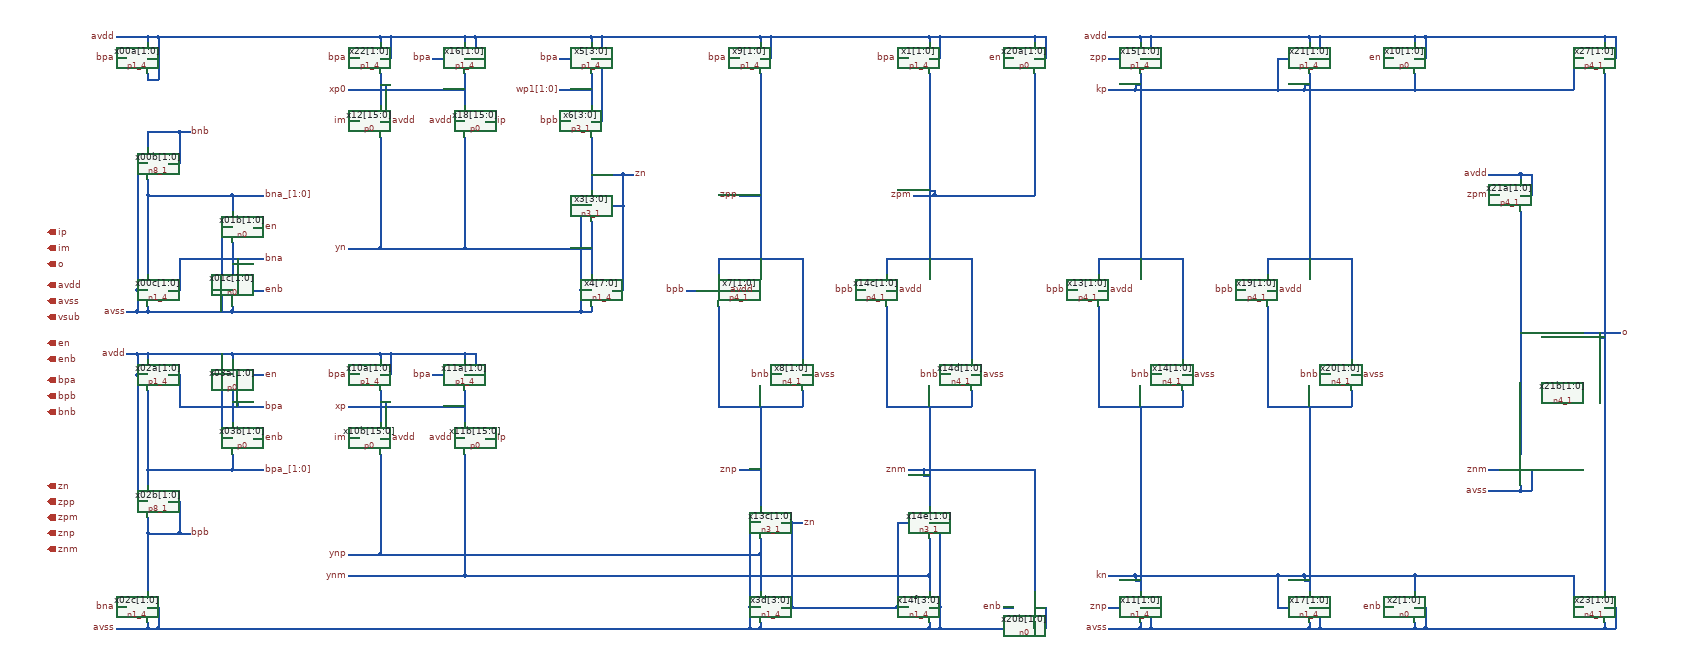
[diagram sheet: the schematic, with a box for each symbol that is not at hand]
v {xschem version=3.4.4 file_version=1.2
}
G {}
K {}
V {}
S {}
E {}
N 220 -760 240 -760 { lab=avss}
N 220 -760 220 -720 { lab=avss}
N 220 -720 240 -720 { lab=avss}
N 240 -730 240 -720 { lab=avss}
N 220 -1000 240 -1000 { lab=avss}
N 240 -1060 240 -1030 { lab=bnb}
N 240 -1060 300 -1060 { lab=bnb}
N 300 -1060 300 -1000 { lab=bnb}
N 280 -1000 300 -1000 { lab=bnb}
N 240 -130 240 -120 { lab=avss}
N 240 -300 300 -300 { lab=bpb}
N 300 -360 300 -300 { lab=bpb}
N 280 -360 300 -360 { lab=bpb}
N 240 -330 240 -300 { lab=bpb}
N 280 -600 300 -600 { lab=bpa}
N 220 -600 240 -600 { lab=avdd}
N 220 -640 220 -600 { lab=avdd}
N 220 -640 240 -640 { lab=avdd}
N 240 -640 240 -630 { lab=avdd}
N 240 -160 260 -160 { lab=avss}
N 260 -160 260 -120 { lab=avss}
N 240 -120 260 -120 { lab=avss}
N 300 -1060 320 -1060 { lab=bnb}
N 300 -300 320 -300 { lab=bpb}
N 220 -360 240 -360 { lab=avdd}
N 200 -640 220 -640 { lab=avdd}
N 200 -720 220 -720 { lab=avss}
N 840 -600 860 -600 { lab=avdd}
N 860 -640 860 -600 { lab=avdd}
N 840 -640 860 -640 { lab=avdd}
N 840 -640 840 -630 { lab=avdd}
N 1440 -160 1460 -160 { lab=zn}
N 1460 -320 1460 -200 { lab=zn}
N 1440 -320 1460 -320 { lab=zn}
N 1400 -130 1400 -120 { lab=avss}
N 1380 -160 1400 -160 { lab=avss}
N 1380 -160 1380 -120 { lab=avss}
N 1380 -120 1400 -120 { lab=avss}
N 1380 -320 1400 -320 { lab=avss}
N 1460 -200 1460 -160 { lab=zn}
N 1380 -320 1380 -160 { lab=avss}
N 1660 -320 1680 -320 { lab=zn}
N 1720 -320 1740 -320 { lab=avss}
N 1720 -160 1740 -160 { lab=avss}
N 1740 -160 1740 -120 { lab=avss}
N 1720 -120 1740 -120 { lab=avss}
N 1720 -130 1720 -120 { lab=avss}
N 1660 -160 1680 -160 { lab=zn}
N 1740 -320 1740 -160 { lab=avss}
N 1660 -320 1660 -160 { lab=zn}
N 1400 -290 1400 -260 { lab=ynp}
N 1400 -260 1400 -190 { lab=ynp}
N 680 -450 680 -260 { lab=ynp}
N 840 -450 840 -220 { lab=ynm}
N 1720 -290 1720 -220 { lab=ynm}
N 1720 -220 1720 -190 { lab=ynm}
N 680 -600 700 -600 { lab=avdd}
N 700 -640 700 -600 { lab=avdd}
N 680 -640 700 -640 { lab=avdd}
N 680 -640 680 -630 { lab=avdd}
N 680 -570 680 -510 { lab=xp}
N 840 -570 840 -510 { lab=xp}
N 700 -640 840 -640 { lab=avdd}
N 620 -600 640 -600 { lab=bpa}
N 780 -600 800 -600 { lab=bpa}
N 620 -540 840 -540 { lab=xp}
N 690 -550 690 -540 { lab=xp}
N 680 -550 690 -550 { lab=xp}
N 820 -480 840 -480 { lab=avdd}
N 680 -480 700 -480 { lab=avdd}
N 1580 -760 1600 -760 { lab=bpb}
N 1740 -600 1760 -600 { lab=bnb}
N 1640 -760 1660 -760 { lab=avdd}
N 1800 -600 1820 -600 { lab=avss}
N 2840 -420 2860 -420 { lab=avss}
N 2860 -420 2860 -380 { lab=avss}
N 2840 -380 2860 -380 { lab=avss}
N 2840 -390 2840 -380 { lab=avss}
N 2840 -940 2860 -940 { lab=avdd}
N 2860 -980 2860 -940 { lab=avdd}
N 2840 -980 2860 -980 { lab=avdd}
N 2840 -980 2840 -970 { lab=avdd}
N 1640 -540 1800 -540 { lab=znm}
N 1640 -730 1640 -540 { lab=znm}
N 1800 -570 1800 -540 { lab=znm}
N 1640 -820 1640 -790 { lab=zpm}
N 1640 -820 1800 -820 { lab=zpm}
N 1800 -820 1800 -630 { lab=zpm}
N 1720 -540 1720 -350 { lab=znm}
N 1540 -160 1660 -160 { lab=zn}
N 1710 -420 1710 -410 { lab=znm}
N 1710 -410 1720 -410 { lab=znm}
N 620 -220 840 -220 { lab=ynm}
N 620 -260 680 -260 { lab=ynp}
N 880 -480 900 -480 { lab=ip}
N 620 -480 640 -480 { lab=im}
N 280 -760 300 -760 { lab=bna}
N 240 -720 400 -720 { lab=avss}
N 300 -820 300 -760 { lab=bna}
N 240 -940 240 -790 { lab=bna_[1:0]}
N 300 -820 460 -820 { lab=bna}
N 400 -850 400 -790 { lab=bna}
N 400 -730 400 -720 { lab=avss}
N 440 -760 460 -760 { lab=enb}
N 440 -880 460 -880 { lab=en}
N 400 -940 400 -910 { lab=bna_[1:0]}
N 380 -880 400 -880 { lab=avss}
N 380 -880 380 -760 { lab=avss}
N 380 -760 400 -760 { lab=avss}
N 380 -760 380 -720 { lab=avss}
N 410 -820 410 -810 { lab=bna}
N 400 -810 410 -810 { lab=bna}
N 220 -1000 220 -760 { lab=avss}
N 240 -970 240 -940 { lab=bna_[1:0]}
N 240 -940 400 -940 { lab=bna_[1:0]}
N 400 -940 460 -940 { lab=bna_[1:0]}
N 240 -640 400 -640 { lab=avdd}
N 400 -640 400 -630 { lab=avdd}
N 400 -570 400 -510 { lab=bpa}
N 300 -600 300 -540 { lab=bpa}
N 300 -540 460 -540 { lab=bpa}
N 380 -640 380 -600 { lab=avdd}
N 380 -600 400 -600 { lab=avdd}
N 380 -480 400 -480 { lab=avdd}
N 380 -600 380 -480 { lab=avdd}
N 400 -450 400 -420 { lab=bpa_[1:0]}
N 240 -420 400 -420 { lab=bpa_[1:0]}
N 240 -570 240 -420 { lab=bpa_[1:0]}
N 240 -420 240 -390 { lab=bpa_[1:0]}
N 220 -600 220 -360 { lab=avdd}
N 440 -600 460 -600 { lab=en}
N 440 -480 460 -480 { lab=enb}
N 410 -550 410 -540 { lab=bpa}
N 400 -550 410 -550 { lab=bpa}
N 180 -160 200 -160 { lab=bna}
N 400 -420 460 -420 { lab=bpa_[1:0]}
N 240 -300 240 -190 { lab=bpb}
N 180 -120 240 -120 { lab=avss}
N 400 -640 680 -640 { lab=avdd}
N 240 -1200 260 -1200 { lab=avdd}
N 260 -1240 260 -1200 { lab=avdd}
N 240 -1240 260 -1240 { lab=avdd}
N 240 -1240 240 -1230 { lab=avdd}
N 180 -1200 200 -1200 { lab=bpa}
N 260 -1200 260 -1160 { lab=avdd}
N 240 -1160 260 -1160 { lab=avdd}
N 240 -1170 240 -1160 { lab=avdd}
N 180 -1240 240 -1240 { lab=avdd}
N 1920 -130 1920 -120 { lab=avss}
N 1940 -160 1940 -120 { lab=avss}
N 1920 -160 1940 -160 { lab=avss}
N 1860 -160 1880 -160 { lab=enb}
N 1860 -1200 1880 -1200 { lab=en}
N 1940 -1240 1940 -1200 { lab=avdd}
N 1920 -1200 1940 -1200 { lab=avdd}
N 1920 -1240 1920 -1230 { lab=avdd}
N 1920 -1240 1940 -1240 { lab=avdd}
N 1660 -1200 1680 -1200 { lab=bpa}
N 1720 -1200 1740 -1200 { lab=avdd}
N 1740 -1240 1740 -1200 { lab=avdd}
N 1720 -1240 1740 -1240 { lab=avdd}
N 1720 -1240 1720 -1230 { lab=avdd}
N 1730 -950 1730 -940 {
lab=zpm}
N 1720 -950 1730 -950 {
lab=zpm}
N 1460 -320 1480 -320 {
lab=zn}
N 1120 -760 1140 -760 { lab=zn}
N 1140 -920 1140 -800 { lab=zn}
N 1120 -920 1140 -920 { lab=zn}
N 1080 -730 1080 -720 { lab=avss}
N 1060 -760 1080 -760 { lab=avss}
N 1060 -760 1060 -720 { lab=avss}
N 1060 -720 1080 -720 { lab=avss}
N 1060 -920 1080 -920 { lab=avss}
N 1140 -800 1140 -760 { lab=zn}
N 1060 -920 1060 -760 { lab=avss}
N 1080 -890 1080 -860 { lab=yn}
N 1080 -860 1080 -790 { lab=yn}
N 1080 -1170 1080 -1110 { lab=wp1[1:0]}
N 1020 -1080 1040 -1080 { lab=bpb}
N 1020 -1200 1040 -1200 { lab=bpa}
N 1080 -1080 1100 -1080 { lab=avdd}
N 1100 -1200 1100 -1080 { lab=avdd}
N 1080 -1200 1100 -1200 { lab=avdd}
N 1100 -1240 1100 -1200 { lab=avdd}
N 1080 -1240 1100 -1240 { lab=avdd}
N 1080 -1240 1080 -1230 { lab=avdd}
N 1020 -1140 1080 -1140 { lab=wp1[1:0]}
N 1080 -980 1140 -980 {
lab=zn}
N 1140 -980 1140 -920 {
lab=zn}
N 1260 -760 1280 -760 { lab=bpb}
N 1420 -600 1440 -600 { lab=bnb}
N 1320 -760 1340 -760 { lab=avdd}
N 1480 -600 1500 -600 { lab=avss}
N 1320 -540 1480 -540 { lab=znp}
N 1320 -730 1320 -540 { lab=znp}
N 1480 -570 1480 -540 { lab=znp}
N 1320 -820 1320 -790 { lab=zpp}
N 1320 -820 1480 -820 { lab=zpp}
N 1480 -820 1480 -630 { lab=zpp}
N 1340 -1200 1360 -1200 { lab=bpa}
N 1400 -1200 1420 -1200 { lab=avdd}
N 1420 -1240 1420 -1200 { lab=avdd}
N 1400 -1240 1420 -1240 { lab=avdd}
N 1400 -1240 1400 -1230 { lab=avdd}
N 1460 -160 1540 -160 {
lab=zn}
N 1400 -540 1400 -350 {
lab=znp}
N 1420 -1240 1720 -1240 {
lab=avdd}
N 1140 -980 1160 -980 {
lab=zn}
N 2120 -160 2140 -160 { lab=avss}
N 2140 -160 2140 -120 { lab=avss}
N 2120 -120 2140 -120 { lab=avss}
N 2060 -160 2080 -160 { lab=znp}
N 1980 -760 2000 -760 { lab=bpb}
N 2140 -600 2160 -600 { lab=bnb}
N 2040 -760 2060 -760 { lab=avdd}
N 2200 -600 2220 -600 { lab=avss}
N 2040 -540 2200 -540 { lab=kn}
N 2040 -730 2040 -540 { lab=kn}
N 2200 -570 2200 -540 { lab=kn}
N 2040 -820 2040 -790 { lab=kp}
N 2040 -820 2200 -820 { lab=kp}
N 2200 -820 2200 -630 { lab=kp}
N 2120 -1200 2140 -1200 { lab=avdd}
N 2140 -1240 2140 -1200 { lab=avdd}
N 2120 -1240 2140 -1240 { lab=avdd}
N 2440 -160 2460 -160 { lab=avss}
N 2460 -160 2460 -120 { lab=avss}
N 2440 -120 2460 -120 { lab=avss}
N 2440 -130 2440 -120 { lab=avss}
N 2380 -160 2400 -160 { lab=kn}
N 2300 -760 2320 -760 { lab=bpb}
N 2460 -600 2480 -600 { lab=bnb}
N 2360 -760 2380 -760 { lab=avdd}
N 2520 -600 2540 -600 { lab=avss}
N 2360 -540 2520 -540 { lab=kn}
N 2360 -730 2360 -540 { lab=kn}
N 2520 -570 2520 -540 { lab=kn}
N 2360 -820 2360 -790 { lab=kp}
N 2360 -820 2520 -820 { lab=kp}
N 2520 -820 2520 -630 { lab=kp}
N 2440 -540 2440 -350 { lab=kn}
N 2380 -1200 2400 -1200 { lab=kp}
N 2440 -1200 2460 -1200 { lab=avdd}
N 2460 -1240 2460 -1200 { lab=avdd}
N 2440 -1240 2460 -1240 { lab=avdd}
N 2440 -1240 2440 -1230 { lab=avdd}
N 3000 -160 3020 -160 { lab=avss}
N 3020 -160 3020 -120 { lab=avss}
N 3000 -120 3020 -120 { lab=avss}
N 3000 -130 3000 -120 { lab=avss}
N 2940 -160 2960 -160 { lab=kn}
N 2940 -1200 2960 -1200 { lab=kp}
N 3000 -1200 3020 -1200 { lab=avdd}
N 3020 -1240 3020 -1200 { lab=avdd}
N 3000 -1240 3020 -1240 { lab=avdd}
N 3000 -1240 3000 -1230 { lab=avdd}
N 2140 -120 2440 -120 {
lab=avss}
N 2140 -1240 2440 -1240 {
lab=avdd}
N 2060 -1240 2120 -1240 { lab=avdd}
N 2120 -1240 2120 -1230 {
lab=avdd}
N 2060 -120 2120 -120 { lab=avss}
N 2120 -130 2120 -120 {
lab=avss}
N 1360 -940 1380 -940 { lab=zpp}
N 1380 -940 1400 -940 {
lab=zpp}
N 1360 -420 1380 -420 { lab=znp}
N 1380 -420 1400 -420 {
lab=znp}
N 2120 -950 2120 -820 {
lab=kp}
N 2120 -1020 2120 -950 {
lab=kp}
N 2120 -1170 2120 -1020 {
lab=kp}
N 2440 -1170 2440 -820 {
lab=kp}
N 3000 -1170 3000 -190 {
lab=o}
N 2440 -350 2440 -190 {
lab=kn}
N 2120 -540 2120 -190 {
lab=kn}
N 1400 -1170 1400 -820 {
lab=zpp}
N 1720 -1170 1720 -820 {
lab=zpm}
N 680 -840 840 -840 {
lab=yn}
N 620 -840 680 -840 {
lab=yn}
N 260 -1240 680 -1240 {
lab=avdd}
N 2060 -1200 2080 -1200 {
lab=zpp}
N 2430 -220 2430 -210 {
lab=kn}
N 2430 -210 2440 -210 {
lab=kn}
N 2380 -220 2380 -160 {
lab=kn}
N 2940 -220 2940 -160 {
lab=kn}
N 1080 -1050 1080 -950 {
lab=zn}
N 2110 -220 2110 -210 {
lab=kn}
N 2110 -210 2120 -210 {
lab=kn}
N 2380 -220 2430 -220 {
lab=kn}
N 2110 -220 2380 -220 {
lab=kn}
N 2060 -220 2110 -220 {
lab=kn}
N 2640 -130 2640 -120 { lab=avss}
N 2660 -160 2660 -120 { lab=avss}
N 2640 -160 2660 -160 { lab=avss}
N 2640 -220 2640 -190 { lab=kn}
N 2580 -160 2600 -160 { lab=enb}
N 2580 -1200 2600 -1200 { lab=en}
N 2660 -1240 2660 -1200 { lab=avdd}
N 2640 -1200 2660 -1200 { lab=avdd}
N 2640 -1240 2640 -1230 { lab=avdd}
N 2640 -1240 2660 -1240 { lab=avdd}
N 2640 -1170 2640 -1140 { lab=kp}
N 2110 -1150 2120 -1150 {
lab=kp}
N 2110 -1150 2110 -1140 {
lab=kp}
N 2060 -1140 2110 -1140 {
lab=kp}
N 2110 -1140 2380 -1140 {
lab=kp}
N 2380 -1200 2380 -1140 {
lab=kp}
N 2380 -1140 2430 -1140 {
lab=kp}
N 2430 -1150 2430 -1140 {
lab=kp}
N 2430 -1150 2440 -1150 {
lab=kp}
N 2430 -1140 2640 -1140 {
lab=kp}
N 2940 -1200 2940 -1140 {
lab=kp}
N 1740 -120 1940 -120 {
lab=avss}
N 1740 -1240 1920 -1240 {
lab=avdd}
N 1690 -940 1730 -940 {
lab=zpm}
N 1730 -940 1920 -940 {
lab=zpm}
N 1920 -1170 1920 -940 {
lab=zpm}
N 1680 -420 1710 -420 {
lab=znm}
N 1710 -420 1920 -420 {
lab=znm}
N 1920 -420 1920 -190 {
lab=znm}
N 2780 -420 2800 -420 { lab=znm}
N 2780 -940 2800 -940 {
lab=zpm}
N 2460 -120 2640 -120 {lab=avss}
N 2640 -120 2660 -120 {lab=avss}
N 2660 -120 3000 -120 {lab=avss}
N 2640 -220 2940 -220 {lab=kn}
N 2430 -220 2640 -220 {lab=kn}
N 2840 -910 2840 -450 {lab=o}
N 2840 -680 3030 -680 {lab=o}
N 2990 -680 2990 -670 {lab=o}
N 2990 -670 3000 -670 {lab=o}
N 2460 -1240 2640 -1240 {lab=avdd}
N 2660 -1240 3000 -1240 {lab=avdd}
N 2640 -1140 2940 -1140 {lab=kp}
N 2780 -980 2840 -980 { lab=avdd}
N 2780 -380 2840 -380 { lab=avss}
N 840 -1200 860 -1200 { lab=avdd}
N 860 -1240 860 -1200 { lab=avdd}
N 840 -1240 860 -1240 { lab=avdd}
N 840 -1240 840 -1230 { lab=avdd}
N 680 -1200 700 -1200 { lab=avdd}
N 700 -1240 700 -1200 { lab=avdd}
N 680 -1240 700 -1240 { lab=avdd}
N 680 -1240 680 -1230 { lab=avdd}
N 680 -1170 680 -1110 { lab=xp0}
N 840 -1170 840 -1110 { lab=xp0}
N 700 -1240 840 -1240 { lab=avdd}
N 620 -1200 640 -1200 { lab=bpa}
N 780 -1200 800 -1200 { lab=bpa}
N 620 -1140 840 -1140 { lab=xp0}
N 690 -1150 690 -1140 { lab=xp0}
N 680 -1150 690 -1150 { lab=xp0}
N 820 -1080 840 -1080 { lab=avdd}
N 680 -1080 700 -1080 { lab=avdd}
N 880 -1080 900 -1080 { lab=ip}
N 620 -1080 640 -1080 { lab=im}
N 680 -1050 680 -840 {
lab=yn}
N 840 -1050 840 -840 {
lab=yn}
N 840 -840 1080 -840 {
lab=yn}
N 400 -720 1060 -720 {
lab=avss}
N 680 -260 1400 -260 {
lab=ynp}
N 840 -220 1720 -220 {
lab=ynm}
N 260 -120 1380 -120 {
lab=avss}
N 1400 -120 1720 -120 {
lab=avss}
N 860 -1240 1080 -1240 {
lab=avdd}
N 1100 -1240 1400 -1240 {
lab=avdd}
C {devices/title.sym} 160 -40 0 0 {name=l6 author="Luis Henrique Rodovalho"}
C {devices/iopin.sym} 50 -770 2 1 {name=pavdd lab=avdd}
C {devices/iopin.sym} 50 -740 2 1 {name=pavss lab=avss}
C {devices/iopin.sym} 50 -870 2 1 {name=pip lab=ip}
C {devices/iopin.sym} 50 -840 2 1 {name=pim lab=im}
C {devices/iopin.sym} 50 -810 2 1 {name=po lab=o}
C {n8_1.sym} 260 -1000 0 1 {name=x00b[1:0]}
C {n1_4.sym} 220 -160 0 0 {name=x02c[1:0]}
C {p8_1.sym} 260 -360 0 1 {name=x02b[1:0]}
C {p1_4.sym} 260 -600 0 1 {name=x02a[1:0]}
C {devices/lab_pin.sym} 320 -1060 2 0 {name=l10 sig_type=std_logic lab=bnb}
C {devices/lab_pin.sym} 460 -820 2 0 {name=l11 sig_type=std_logic lab=bna}
C {devices/lab_pin.sym} 320 -300 2 0 {name=l12 sig_type=std_logic lab=bpb}
C {devices/lab_pin.sym} 460 -540 2 0 {name=l13 sig_type=std_logic lab=bpa}
C {devices/lab_pin.sym} 200 -640 2 1 {name=lavdd1 sig_type=std_logic lab=avdd}
C {devices/lab_pin.sym} 200 -720 2 1 {name=lavss0 sig_type=std_logic lab=avss}
C {p0.sym} 660 -480 0 0 {name=x10b[15:0]}
C {p1_4.sym} 820 -600 0 0 {name=x11a[1:0]}
C {p0.sym} 860 -480 0 1 {name=x11b[15:0]}
C {n3_1.sym} 1420 -320 0 1 {name=x13c[1:0]}
C {n1_4.sym} 1420 -160 0 1 {name=x3d[3:0]}
C {n1_4.sym} 1700 -160 0 0 {name=x14f[3:0]}
C {n3_1.sym} 1700 -320 0 0 {name=x14e[1:0]}
C {p1_4.sym} 660 -600 0 0 {name=x10a[1:0]}
C {devices/lab_pin.sym} 620 -600 2 1 {name=l19 sig_type=std_logic lab=bpa}
C {devices/lab_pin.sym} 780 -600 2 1 {name=l20 sig_type=std_logic lab=bpa}
C {devices/lab_pin.sym} 620 -540 2 1 {name=lxp sig_type=std_logic lab=xp}
C {devices/lab_pin.sym} 820 -480 2 1 {name=lavdd3 sig_type=std_logic lab=avdd}
C {devices/lab_pin.sym} 700 -480 2 0 {name=lavdd2 sig_type=std_logic lab=avdd}
C {p4_1.sym} 1620 -760 0 0 {name=x14c[1:0]}
C {devices/lab_pin.sym} 1580 -760 2 1 {name=l31 sig_type=std_logic lab=bpb}
C {n4_1.sym} 1780 -600 0 0 {name=x14d[1:0]}
C {devices/lab_pin.sym} 1740 -600 2 1 {name=l32 sig_type=std_logic lab=bnb}
C {devices/lab_pin.sym} 1660 -760 2 0 {name=lavdd4 sig_type=std_logic lab=avdd}
C {devices/lab_pin.sym} 1820 -600 2 0 {name=lavss4 sig_type=std_logic lab=avss}
C {n4_1.sym} 2820 -420 0 0 {name=x21b[1:0]}
C {p4_1.sym} 2820 -940 0 0 {name=x21a[1:0]}
C {devices/lab_pin.sym} 180 -120 2 1 {name=lavss1 sig_type=std_logic lab=avss}
C {devices/lab_pin.sym} 180 -1240 2 1 {name=lavdd0 sig_type=std_logic lab=avdd}
C {devices/lab_pin.sym} 900 -480 2 0 {name=l4 sig_type=std_logic lab=ip}
C {devices/lab_pin.sym} 620 -480 2 1 {name=l5 sig_type=std_logic lab=im}
C {devices/lab_pin.sym} 620 -220 2 1 {name=lynm sig_type=std_logic lab=ynm}
C {devices/lab_pin.sym} 620 -260 2 1 {name=lynp sig_type=std_logic lab=ynp}
C {devices/lab_pin.sym} 1480 -320 2 0 {name=lznm sig_type=std_logic lab=zn}
C {devices/lab_pin.sym} 1680 -420 2 1 {name=lznp sig_type=std_logic lab=znm}
C {n0.sym} 420 -760 0 1 {name=x01c[1:0]}
C {n0.sym} 420 -880 0 1 {name=x01b[1:0]}
C {n1_4.sym} 260 -760 0 1 {name=x00c[1:0]}
C {devices/lab_pin.sym} 460 -760 2 0 {name=l46 sig_type=std_logic lab=enb}
C {devices/lab_pin.sym} 460 -880 2 0 {name=l47 sig_type=std_logic lab=en}
C {devices/lab_pin.sym} 460 -940 2 0 {name=l9 sig_type=std_logic lab=bna_[1:0]}
C {p0.sym} 420 -600 0 1 {name=x03a[1:0]}
C {p0.sym} 420 -480 0 1 {name=x03b[1:0]}
C {devices/lab_pin.sym} 460 -480 2 0 {name=l48 sig_type=std_logic lab=enb}
C {devices/lab_pin.sym} 460 -600 2 0 {name=l49 sig_type=std_logic lab=en}
C {devices/lab_pin.sym} 180 -160 2 1 {name=l50 sig_type=std_logic lab=bna}
C {devices/lab_pin.sym} 460 -420 2 0 {name=l51 sig_type=std_logic lab=bpa_[1:0]}
C {devices/iopin.sym} 50 -590 2 1 {name=pbpa lab=bpa}
C {devices/iopin.sym} 50 -560 2 1 {name=pbpb lab=bpb}
C {devices/iopin.sym} 50 -530 2 1 {name=pbnb lab=bnb}
C {devices/iopin.sym} 50 -330 2 1 {name=pzpm lab=zpm}
C {devices/iopin.sym} 50 -360 2 1 {name=pzpp lab=zpp}
C {devices/iopin.sym} 50 -270 2 1 {name=pznm lab=znm}
C {devices/iopin.sym} 50 -300 2 1 {name=pznp lab=znp}
C {p1_4.sym} 220 -1200 0 0 {name=x00a[1:0]}
C {devices/lab_pin.sym} 180 -1200 2 1 {name=l16 sig_type=std_logic lab=bpa}
C {n0.sym} 1900 -160 0 0 {name=x20b[1:0]}
C {devices/lab_pin.sym} 1860 -160 2 1 {name=l21 sig_type=std_logic lab=enb}
C {p0.sym} 1900 -1200 0 0 {name=x20a[1:0]}
C {devices/lab_pin.sym} 1860 -1200 2 1 {name=l26 sig_type=std_logic lab=en}
C {devices/iopin.sym} 50 -390 2 1 {name=pynp1 lab=zn}
C {devices/iopin.sym} 50 -710 2 1 {name=pvsub lab=vsub}
C {devices/iopin.sym} 50 -660 2 1 {name=pen lab=en}
C {devices/iopin.sym} 50 -630 2 1 {name=penb lab=enb}
C {p1_4.sym} 1700 -1200 0 0 {name=x1[1:0]}
C {devices/lab_pin.sym} 1660 -1200 2 1 {name=l2 sig_type=std_logic lab=bpa}
C {devices/lab_pin.sym} 1690 -940 2 1 {name=lznp1 sig_type=std_logic lab=zpm}
C {n3_1.sym} 1100 -920 0 1 {name=x3[3:0]}
C {n1_4.sym} 1100 -760 0 1 {name=x4[7:0]}
C {p1_4.sym} 1060 -1200 0 0 {name=x5[3:0]}
C {p3_1.sym} 1060 -1080 0 0 {name=x6[3:0]}
C {devices/lab_pin.sym} 1020 -1080 2 1 {name=l7 sig_type=std_logic lab=bpb}
C {devices/lab_pin.sym} 1020 -1200 2 1 {name=l8 sig_type=std_logic lab=bpa}
C {devices/lab_pin.sym} 1020 -1140 2 1 {name=lwp2 sig_type=std_logic lab=wp1[1:0]}
C {p4_1.sym} 1300 -760 0 0 {name=x7[1:0]}
C {devices/lab_pin.sym} 1260 -760 2 1 {name=l14 sig_type=std_logic lab=bpb}
C {n4_1.sym} 1460 -600 0 0 {name=x8[1:0]}
C {devices/lab_pin.sym} 1420 -600 2 1 {name=l15 sig_type=std_logic lab=bnb}
C {devices/lab_pin.sym} 1340 -760 2 0 {name=lavdd5 sig_type=std_logic lab=avdd}
C {devices/lab_pin.sym} 1500 -600 2 0 {name=lavss3 sig_type=std_logic lab=avss}
C {p1_4.sym} 1380 -1200 0 0 {name=x9[1:0]}
C {devices/lab_pin.sym} 1340 -1200 2 1 {name=l23 sig_type=std_logic lab=bpa}
C {devices/lab_pin.sym} 1160 -980 0 1 {name=lznm1 sig_type=std_logic lab=zn}
C {n1_4.sym} 2100 -160 0 0 {name=x11[1:0]}
C {p4_1.sym} 2020 -760 0 0 {name=x13[1:0]}
C {devices/lab_pin.sym} 1980 -760 2 1 {name=l24 sig_type=std_logic lab=bpb}
C {n4_1.sym} 2180 -600 0 0 {name=x14[1:0]}
C {devices/lab_pin.sym} 2140 -600 2 1 {name=l25 sig_type=std_logic lab=bnb}
C {devices/lab_pin.sym} 2060 -760 2 0 {name=lavdd6 sig_type=std_logic lab=avdd}
C {devices/lab_pin.sym} 2220 -600 2 0 {name=lavss5 sig_type=std_logic lab=avss}
C {p1_4.sym} 2100 -1200 0 0 {name=x15[1:0]}
C {n1_4.sym} 2420 -160 0 0 {name=x17[1:0]}
C {p4_1.sym} 2340 -760 0 0 {name=x19[1:0]}
C {devices/lab_pin.sym} 2300 -760 2 1 {name=l29 sig_type=std_logic lab=bpb}
C {n4_1.sym} 2500 -600 0 0 {name=x20[1:0]}
C {devices/lab_pin.sym} 2460 -600 2 1 {name=l30 sig_type=std_logic lab=bnb}
C {devices/lab_pin.sym} 2380 -760 2 0 {name=lavdd7 sig_type=std_logic lab=avdd}
C {devices/lab_pin.sym} 2540 -600 2 0 {name=lavss6 sig_type=std_logic lab=avss}
C {p1_4.sym} 2420 -1200 0 0 {name=x21[1:0]}
C {n4_1.sym} 2980 -160 0 0 {name=x23[1:0]}
C {p4_1.sym} 2980 -1200 0 0 {name=x27[1:0]}
C {devices/lab_pin.sym} 2060 -1240 2 1 {name=lavdd8 sig_type=std_logic lab=avdd}
C {devices/lab_pin.sym} 2060 -120 2 1 {name=lavss7 sig_type=std_logic lab=avss}
C {devices/lab_pin.sym} 2060 -1200 2 1 {name=l27 sig_type=std_logic lab=zpp}
C {devices/lab_pin.sym} 2060 -160 2 1 {name=l28 sig_type=std_logic lab=znp
}
C {devices/lab_pin.sym} 1360 -940 2 1 {name=l33 sig_type=std_logic lab=zpp}
C {devices/lab_pin.sym} 1360 -420 2 1 {name=l34 sig_type=std_logic lab=znp}
C {devices/lab_pin.sym} 3030 -680 2 0 {name=l35 sig_type=std_logic lab=o}
C {devices/lab_pin.sym} 2060 -1140 2 1 {name=l36 sig_type=std_logic lab=kp}
C {devices/lab_pin.sym} 2060 -220 2 1 {name=l37 sig_type=std_logic lab=kn}
C {devices/lab_pin.sym} 620 -840 2 1 {name=lynp1 sig_type=std_logic lab=yn}
C {n0.sym} 2620 -160 0 0 {name=x2[1:0]}
C {devices/lab_pin.sym} 2580 -160 2 1 {name=l1 sig_type=std_logic lab=enb}
C {p0.sym} 2620 -1200 0 0 {name=x10[1:0]}
C {devices/lab_pin.sym} 2580 -1200 2 1 {name=l22 sig_type=std_logic lab=en}
C {devices/lab_pin.sym} 2780 -420 2 1 {name=l38 sig_type=std_logic lab=znm
}
C {devices/lab_pin.sym} 2780 -940 2 1 {name=l39 sig_type=std_logic lab=zpm
}
C {devices/lab_pin.sym} 2780 -980 2 1 {name=lavdd9 sig_type=std_logic lab=avdd}
C {devices/lab_pin.sym} 2780 -380 2 1 {name=lavss2 sig_type=std_logic lab=avss}
C {p0.sym} 660 -1080 0 0 {name=x12[15:0]}
C {p1_4.sym} 820 -1200 0 0 {name=x16[1:0]}
C {p0.sym} 860 -1080 0 1 {name=x18[15:0]}
C {p1_4.sym} 660 -1200 0 0 {name=x22[1:0]}
C {devices/lab_pin.sym} 620 -1200 2 1 {name=l3 sig_type=std_logic lab=bpa}
C {devices/lab_pin.sym} 780 -1200 2 1 {name=l17 sig_type=std_logic lab=bpa}
C {devices/lab_pin.sym} 620 -1140 2 1 {name=lxp1 sig_type=std_logic lab=xp0}
C {devices/lab_pin.sym} 820 -1080 2 1 {name=lavdd10 sig_type=std_logic lab=avdd}
C {devices/lab_pin.sym} 700 -1080 2 0 {name=lavdd11 sig_type=std_logic lab=avdd}
C {devices/lab_pin.sym} 900 -1080 2 0 {name=l18 sig_type=std_logic lab=ip}
C {devices/lab_pin.sym} 620 -1080 2 1 {name=l40 sig_type=std_logic lab=im}
